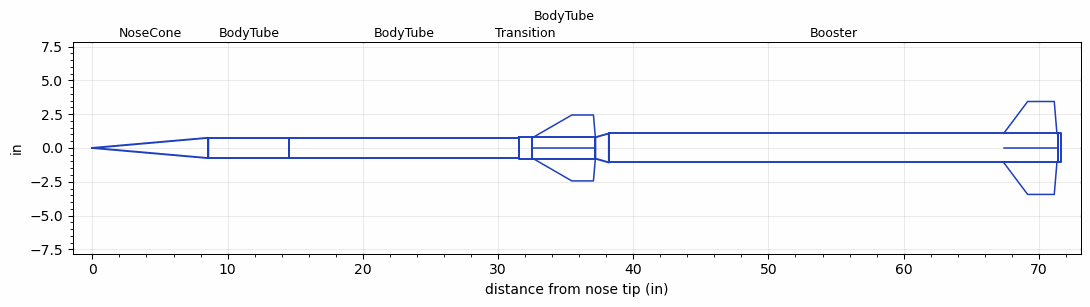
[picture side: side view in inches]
<RASAeroDocument>
 <FileVersion>2</FileVersion>
 <RocketDesign>
  <NoseCone>
   <Length>8.57</Length>
   <Diameter>1.5</Diameter>
   <Shape>Conical</Shape>
   <BluntRadius>0.065</BluntRadius>
   <Location>0</Location>
  </NoseCone>
  <BodyTube>
   <Length>6</Length>
   <Diameter>1.5</Diameter>
   <Location>8.57</Location>
  </BodyTube>
  <BodyTube>
   <Length>16.98</Length>
   <Diameter>1.5</Diameter>
   <Location>14.57</Location>
  </BodyTube>
  <Transition>
   <Length>1</Length>
   <Diameter>1.575</Diameter>
   <Location>31.55</Location>
   <RearDiameter>1.575</RearDiameter>
  </Transition>
  <BodyTube>
   <Length>4.65</Length>
   <Diameter>1.575</Diameter>
   <Location>32.55</Location>
   <Fin>
    <Count>4</Count>
    <Chord>4.6</Chord>
    <Span>1.65</Span>
    <SweepDistance>2.857</SweepDistance>
    <TipChord>1.6</TipChord>
    <Thickness>0.1</Thickness>
    <LERadius>0.024</LERadius>
    <Location>4.6</Location>
    <AirfoilSection>Double Wedge</AirfoilSection>
    <FX1>0.75</FX1>
    <FX3>0.25</FX3>
   </Fin>
  </BodyTube>
  <Booster>
   <Length>33.2</Length>
   <Diameter>2.15</Diameter>
   <InsideDiameter>1.575</InsideDiameter>
   <RailGuideDiameter>0.3</RailGuideDiameter>
   <RailGuideHeight>0.3</RailGuideHeight>
   <Location>37.2</Location>
   <ShoulderLength>1</ShoulderLength>
   <BoattailLength>0.25</BoattailLength>
   <BoattailRearDiameter>2.15</BoattailRearDiameter>
   <Fin>
    <Count>4</Count>
    <Chord>3.937</Chord>
    <Span>2.362</Span>
    <SweepDistance>1.772</SweepDistance>
    <TipChord>1.969</TipChord>
    <Thickness>0.125</Thickness>
    <LERadius>0.065</LERadius>
    <Location>4</Location>
    <AirfoilSection>Hexagonal</AirfoilSection>
    <FX1>0.5</FX1>
    <FX3>0.5</FX3>
   </Fin>
  </Booster>
  <Surface>Camouflage Paint</Surface>
  <ModifiedBarrowman>True</ModifiedBarrowman>
  <Turbulence>True</Turbulence>
  <UseBooster1>False</UseBooster1>
  <UseBooster2>False</UseBooster2>
 </RocketDesign>
 <LaunchSite>
  <Altitude>2000</Altitude>
  <Pressure>29.9</Pressure>
  <RodAngle>5</RodAngle>
  <RodLength>15</RodLength>
  <Temperature>110</Temperature>
  <WindSpeed>10</WindSpeed>
 </LaunchSite>
 <Recovery>
  <Altitude1>1000</Altitude1>
  <Altitude2>1000</Altitude2>
  <DeviceType1>None</DeviceType1>
  <DeviceType2>None</DeviceType2>
  <Event1>False</Event1>
  <Event2>False</Event2>
  <Size1>1</Size1>
  <Size2>1</Size2>
  <EventType1>None</EventType1>
  <EventType2>None</EventType2>
  <CD1>1.33</CD1>
  <CD2>1.33</CD2>
 </Recovery>
 <SimulationList>
  <Simulation>
   <SustainerEngine>J360  (Walter)</SustainerEngine>
   <SustainerLaunchWt>3.33</SustainerLaunchWt>
   <SustainerNozzleDiameter>1.325</SustainerNozzleDiameter>
   <SustainerCG>21.86</SustainerCG>
   <SustainerIgnitionDelay>8</SustainerIgnitionDelay>
   <Booster1Engine>L416SW  (Walter)</Booster1Engine>
   <Booster1LaunchWt>9.8</Booster1LaunchWt>
   <Booster1SeparationDelay>0</Booster1SeparationDelay>
   <Booster1IgnitionDelay>0</Booster1IgnitionDelay>
   <Booster1CG>48.3</Booster1CG>
   <Booster1NozzleDiameter>2</Booster1NozzleDiameter>
   <IncludeBooster1>True</IncludeBooster1>
   <Booster2Delay>0</Booster2Delay>
   <IncludeBooster2>False</IncludeBooster2>
   <TimetoApogee>60.81689</TimetoApogee>
   <MaxAltitude>62257.66</MaxAltitude>
   <MaxVelocity>3298.059</MaxVelocity>
   <OptimumWt>3.475688</OptimumWt>
   <OptimumMaxAlt>3.475688</OptimumMaxAlt>
  </Simulation>
 </SimulationList>
</RASAeroDocument>
